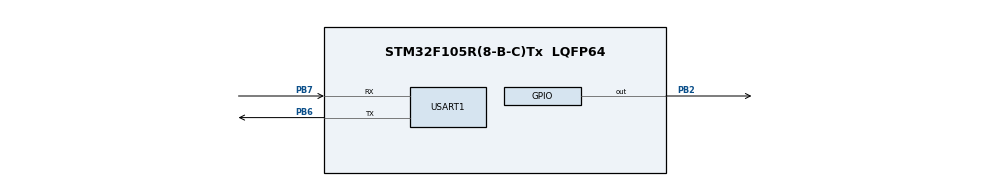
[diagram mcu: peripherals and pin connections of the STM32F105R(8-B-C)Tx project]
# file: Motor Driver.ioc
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Mcu.Family=STM32F1
Mcu.Name=STM32F105R(8-B-C)Tx
Mcu.Package=LQFP64
NVIC.PriorityGroup=NVIC_PRIORITYGROUP_4
NVIC.USART1_IRQn=true\:0\:0\:false\:false\:true\:true\:true\:true
PA13.Mode=Serial_Wire
PA13.Signal=SYS_JTMS-SWDIO
PA14.Mode=Serial_Wire
PA14.Signal=SYS_JTCK-SWCLK
PB2.Signal=GPIO_Output
PB6.Mode=Asynchronous
PB6.Signal=USART1_TX
PB7.Mode=Asynchronous
PB7.Signal=USART1_RX
PD0-OSC_IN.Mode=HSE-External-Oscillator
PD0-OSC_IN.Signal=RCC_OSC_IN
PD1-OSC_OUT.Mode=HSE-External-Oscillator
PD1-OSC_OUT.Signal=RCC_OSC_OUT
ProjectManager.HeapSize=0x200
ProjectManager.StackSize=0x400
ProjectManager.TargetToolchain=STM32CubeIDE
RCC.AHBFreq_Value=8000000
RCC.APB1Freq_Value=8000000
RCC.APB1TimFreq_Value=8000000
RCC.APB2Freq_Value=8000000
RCC.APB2TimFreq_Value=8000000
RCC.HCLKFreq_Value=8000000
RCC.SYSCLKFreq_VALUE=8000000
RCC.SYSCLKSource=RCC_SYSCLKSOURCE_HSE
RCC.USBFreq_Value=10666666.666666666
USART1.VirtualMode=VM_ASYNC
board=custom

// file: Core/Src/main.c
/* USER CODE BEGIN Header */
/**
  ******************************************************************************
  * @file           : main.c
  * @brief          : Main program body
  ******************************************************************************
  * @attention
  *
  * Copyright (c) 2026 STMicroelectronics.
  * All rights reserved.
  *
  * This software is licensed under terms that can be found in the LICENSE file
  * in the root directory of this software component.
  * If no LICENSE file comes with this software, it is provided AS-IS.
  *
  ******************************************************************************
  */
/* USER CODE END Header */
#include "main.h"

/* USER CODE BEGIN Includes */
#include <string.h>
#include <stdio.h>
/* USER CODE END Includes */

/* USER CODE BEGIN PD */
#define UART_BUFFER_SIZE 64
/* USER CODE END PD */

UART_HandleTypeDef huart1;

/* USER CODE BEGIN PV */
uint8_t rx_data;
char command_buffer[UART_BUFFER_SIZE];
uint8_t command_index = 0;
uint8_t command_ready = 0;

/* LED control variables */
volatile uint16_t blink_delay = 500;  /* Default 500ms */
volatile uint8_t led_state = 0;
/* USER CODE END PV */

void SystemClock_Config(void);
static void MX_GPIO_Init(void);
static void MX_USART1_UART_Init(void);
/* USER CODE BEGIN PFP */
void Process_Command(char *cmd);
void UART_Send_Response(char *response);
/* USER CODE END PFP */

/* USER CODE BEGIN 0 */

/**
  * @brief  Process received commands from UART
  * @param  cmd: Command string
  * @retval None
  */
void Process_Command(char *cmd) {
    char response[UART_BUFFER_SIZE];
    int value;

    /* Command format:
     * "BLINK=XXX" - Set blink delay in milliseconds (50-2000)
     * "GET"       - Get current blink delay
     * "STATUS"    - Get status
     * "INIT"      - Initialize connection
     */

    if (strncmp(cmd, "BLINK=", 6) == 0) {
        value = atoi(cmd + 6);

        /* Validate and limit blink delay */
        if (value < 50) value = 50;
        if (value > 2000) value = 2000;

        blink_delay = value;

        sprintf(response, "BLINK:%d\r\n", blink_delay);
        UART_Send_Response(response);
    }
    else if (strcmp(cmd, "GET") == 0) {
        sprintf(response, "BLINK:%d\r\n", blink_delay);
        UART_Send_Response(response);
    }
    else if (strcmp(cmd, "STATUS") == 0) {
        sprintf(response, "READY:LED_TEST\r\n");
        UART_Send_Response(response);
    }
    else if (strcmp(cmd, "INIT") == 0) {
        sprintf(response, "READY:STM32F105_LED_TEST\r\n");
        UART_Send_Response(response);
    }
    else {
        UART_Send_Response("ERROR:UNKNOWN_COMMAND\r\n");
    }
}

/**
  * @brief  Send response via UART
  * @param  response: String to send
  * @retval None
  */
void UART_Send_Response(char *response) {
    HAL_UART_Transmit(&huart1, (uint8_t*)response, strlen(response), 100);
}

/**
  * @brief  UART RX Complete callback
  * @param  huart: UART handle
  * @retval None
  */
void HAL_UART_RxCpltCallback(UART_HandleTypeDef *huart) {
    if (huart->Instance == USART1) {
        if (rx_data == '\n' || rx_data == '\r') {
            command_buffer[command_index] = '\0';
            command_ready = 1;
        } else {
            command_buffer[command_index++] = rx_data;
            if (command_index >= UART_BUFFER_SIZE - 1) {
                command_index = 0;
            }
        }
        HAL_UART_Receive_IT(&huart1, &rx_data, 1);
    }
}

/* USER CODE END 0 */

int main(void)
{

  /* MCU Configuration--------------------------------------------------------*/

  /* Reset of all peripherals, Initializes the Flash interface and the Systick. */
  HAL_Init();

  /* Configure the system clock */
  SystemClock_Config();

  /* Initialize all configured peripherals */
  MX_GPIO_Init();
  MX_USART1_UART_Init();
  /* USER CODE BEGIN 2 */

  /* Start UART reception in interrupt mode */
  HAL_UART_Receive_IT(&huart1, &rx_data, 1);

  uint32_t last_toggle = 0;

  /* USER CODE END 2 */

  /* Infinite loop */
  /* USER CODE BEGIN WHILE */
  while (1)
  {
    /* Process any received commands */
    if (command_ready) {
        Process_Command((char*)command_buffer);
        command_ready = 0;
        command_index = 0;
        memset(command_buffer, 0, UART_BUFFER_SIZE);
    }

    /* LED blinking based on blink_delay from GUI */
    if (HAL_GetTick() - last_toggle >= blink_delay) {
        last_toggle = HAL_GetTick();
        led_state = !led_state;
        HAL_GPIO_WritePin(LED_PORT, LED_PIN, led_state ? GPIO_PIN_SET : GPIO_PIN_RESET);
    }
    /* USER CODE END WHILE */

  }
}

void SystemClock_Config(void)
{
  RCC_OscInitTypeDef RCC_OscInitStruct = {0};
  RCC_ClkInitTypeDef RCC_ClkInitStruct = {0};

  /** Initializes the RCC Oscillators according to the specified parameters
  * in the RCC_OscInitTypeDef structure.
  */
  RCC_OscInitStruct.OscillatorType = RCC_OSCILLATORTYPE_HSE;
  RCC_OscInitStruct.HSEState = RCC_HSE_ON;
  RCC_OscInitStruct.HSEPredivValue = RCC_HSE_PREDIV_DIV1;
  RCC_OscInitStruct.HSIState = RCC_HSI_ON;
  RCC_OscInitStruct.PLL.PLLState = RCC_PLL_ON;
  RCC_OscInitStruct.PLL.PLLSource = RCC_PLLSOURCE_HSE;
  RCC_OscInitStruct.PLL.PLLMUL = RCC_PLL_MUL9;
  if (HAL_RCC_OscConfig(&RCC_OscInitStruct) != HAL_OK)
  {
    Error_Handler();
  }

  /** Initializes the CPU, AHB and APB buses clocks
  */
  RCC_ClkInitStruct.ClockType = RCC_CLOCKTYPE_HCLK | RCC_CLOCKTYPE_SYSCLK
                              | RCC_CLOCKTYPE_PCLK1 | RCC_CLOCKTYPE_PCLK2;
  RCC_ClkInitStruct.SYSCLKSource = RCC_SYSCLKSOURCE_PLLCLK;
  RCC_ClkInitStruct.AHBCLKDivider = RCC_SYSCLK_DIV1;
  RCC_ClkInitStruct.APB1CLKDivider = RCC_HCLK_DIV2;
  RCC_ClkInitStruct.APB2CLKDivider = RCC_HCLK_DIV1;

  if (HAL_RCC_ClockConfig(&RCC_ClkInitStruct, FLASH_LATENCY_2) != HAL_OK)
  {
    Error_Handler();
  }
}

static void MX_USART1_UART_Init(void)
{

  huart1.Instance = USART1;
  huart1.Init.BaudRate = 115200;
  huart1.Init.WordLength = UART_WORDLENGTH_8B;
  huart1.Init.StopBits = UART_STOPBITS_1;
  huart1.Init.Parity = UART_PARITY_NONE;
  huart1.Init.Mode = UART_MODE_TX_RX;
  huart1.Init.HwFlowCtl = UART_HWCONTROL_NONE;
  huart1.Init.OverSampling = UART_OVERSAMPLING_16;
  if (HAL_UART_Init(&huart1) != HAL_OK)
  {
    Error_Handler();
  }
}

static void MX_GPIO_Init(void)
{
  GPIO_InitTypeDef GPIO_InitStruct = {0};

  /* GPIO Ports Clock Enable */
  __HAL_RCC_GPIOB_CLK_ENABLE();

  /*Configure GPIO pin : PB2 */
  GPIO_InitStruct.Pin = GPIO_PIN_2;
  GPIO_InitStruct.Mode = GPIO_MODE_OUTPUT_PP;
  GPIO_InitStruct.Pull = GPIO_NOPULL;
  GPIO_InitStruct.Speed = GPIO_SPEED_FREQ_LOW;
  HAL_GPIO_Init(GPIOB, &GPIO_InitStruct);

}

void Error_Handler(void)
{
  /* USER CODE BEGIN Error_Handler_Debug */
  /* User can add his own implementation to report the HAL error return state */
  __disable_irq();
  while (1)
  {
    /* Toggle LED rapidly to indicate error */
    HAL_GPIO_TogglePin(GPIOB, GPIO_PIN_2);
    HAL_Delay(100);
  }
  /* USER CODE END Error_Handler_Debug */
}
